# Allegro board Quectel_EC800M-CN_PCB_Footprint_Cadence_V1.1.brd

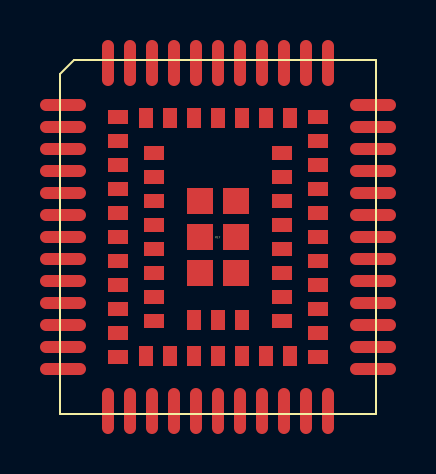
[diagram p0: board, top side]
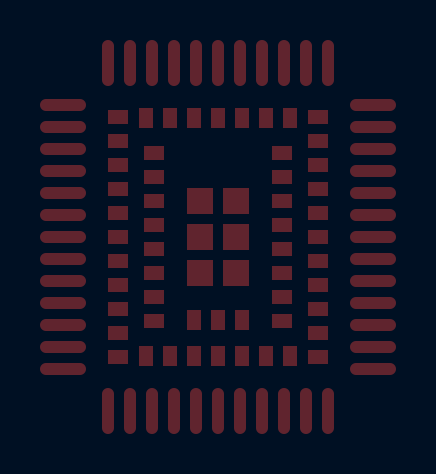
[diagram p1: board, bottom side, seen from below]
No outline. copper layers: TOP, BOTTOM. Coordinates in mm from the lowest, leftmost part position.

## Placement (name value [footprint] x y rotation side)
REF  -  [unnamed]  0 0 0 top

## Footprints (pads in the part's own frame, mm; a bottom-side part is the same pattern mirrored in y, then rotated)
unnamed
  oval 2.3x0.6 smd: 1(-7.75,6.6) 2(-7.75,5.5) 3(-7.75,4.4) 4(-7.75,3.3) 5(-7.75,2.2) 6(-7.75,1.1) 7(-7.75,0) 8(-7.75,-1.1) 9(-7.75,-2.2) 10(-7.75,-3.3) 11(-7.75,-4.4) 12(-7.75,-5.5) 13(-7.75,-6.6) 23(7.75,-6.6) 24(7.75,-5.5) 25(7.75,-4.4) 26(7.75,-3.3) 27(7.75,-2.2) 28(7.75,-1.1) 29(7.75,0) 30(7.75,1.1) 31(7.75,2.2) 32(7.75,3.3) 33(7.75,4.4) 34(7.75,5.5) 35(7.75,6.6)
  oval 0.6x2.3 smd: 14(-4.4,-8.7) 15(-3.3,-8.7) 16(-2.2,-8.7) 17(-1.1,-8.7) 18(0,-8.7) 19(1.1,-8.7) 20(2.2,-8.7) 21(3.3,-8.7) 22(4.4,-8.7) 36(4.4,8.7) 37(3.3,8.7) 38(2.2,8.7) 39(1.1,8.7) 40(0,8.7) 41(-1.1,8.7) 42(-2.2,8.7) 43(-3.3,8.7) 44(-4.4,8.7) 95(-5.5,-8.7) 96(5.5,-8.7) 97(5.5,8.7) 98(-5.5,8.7)
  rect 1x0.7 smd: 45(-5,4.8) 46(-5,3.6) 47(-5,2.4) 48(-5,1.2) 49(-5,0) 50(-5,-1.2) 51(-5,-2.4) 52(-5,-3.6) 53(-5,-4.8) 59(5,-4.8) 60(5,-3.6) 61(5,-2.4) 62(5,-1.2) 63(5,0) 64(5,1.2) 65(5,2.4) 66(5,3.6) 67(5,4.8) 73(-3.2,4.2) 74(-3.2,3) 75(-3.2,1.8) 76(-3.2,0.6) 77(-3.2,-0.6) 78(-3.2,-1.8) 79(-3.2,-3) 80(-3.2,-4.2) 81(3.2,-4.2) 82(3.2,-3) 83(3.2,-1.8) 84(3.2,-0.6) 85(3.2,0.6) 86(3.2,1.8) 87(3.2,3) 88(3.2,4.2) 99(-5,6) 100(-5,-6) 103(5,-6) 104(5,6)
  rect 0.7x1 smd: 54(-2.4,-5.95) 55(-1.2,-5.95) 56(0,-5.95) 57(1.2,-5.95) 58(2.4,-5.95) 68(2.4,5.95) 69(1.2,5.95) 70(0,5.95) 71(-1.2,5.95) 72(-2.4,5.95) 101(-3.6,-5.95) 102(3.6,-5.95) 105(3.6,5.95) 106(-3.6,5.95) 107(-1.2,-4.15) 108(0,-4.15) 109(1.2,-4.15)
  rect 1.3x1.3 smd: 89(-0.9,1.8) 90(-0.9,0) 91(-0.9,-1.8) 92(0.9,-1.8) 93(0.9,0) 94(0.9,1.8)

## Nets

Pads without a net: REF 1 2 3 4 5 6 7 8 9 10 11 12 13 14 15 16 17 18 19 20 21 22 23 24 25 26 27 28 29 30 31 32 33 34 35 36 37 38 39 40 41 42 43 44 45 46 47 48 49 50 51 52 53 54 55 56 57 58 59 60 61 62 63 64 65 66 67 68 69 70 71 72 73 74 75 76 77 78 79 80 81 82 83 84 85 86 87 88 89 90 91 92 93 94 95 96 97 98 99 100 101 102 103 104 105 106 107 108 109
